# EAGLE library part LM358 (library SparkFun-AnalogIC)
Jellybean op-amp

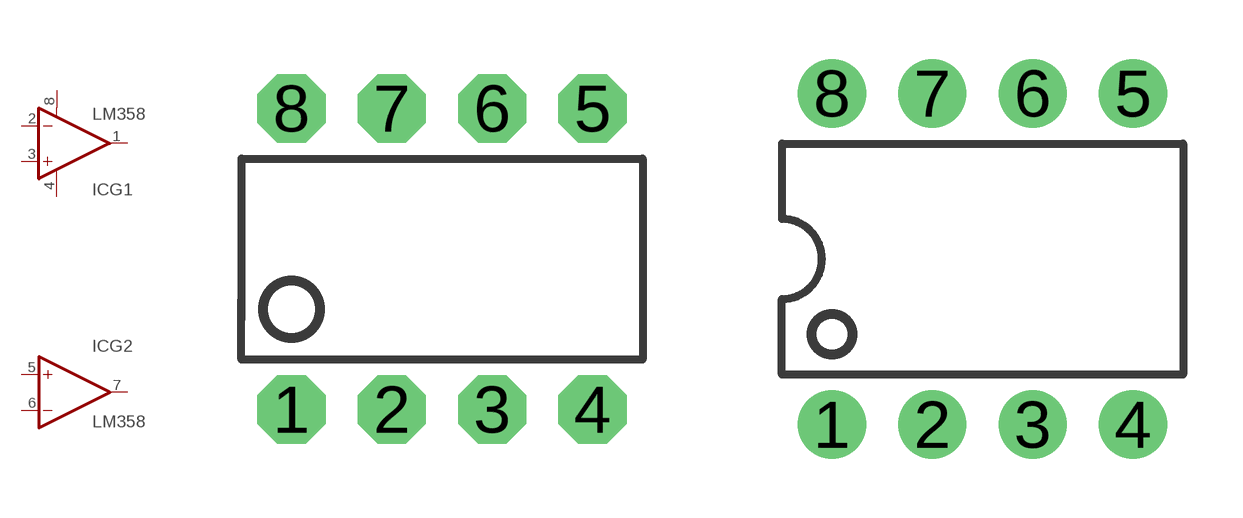
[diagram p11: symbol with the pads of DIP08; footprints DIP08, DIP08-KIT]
Designator prefix IC; gates G1=OP-AMP+- G2=OP-AMP

## LM358 (PROD_ID: IC-09172)  [DIP08]
1  G1:OUT  out
2  G1:-IN  in
3  G1:+IN  in
4  G1:V-  pwr
5  G2:+IN  in
6  G2:-IN  in
7  G2:OUT  out
8  G1:V+  pwr

## LM358KIT (PROD_ID: IC-09172)  [DIP08-KIT]
Pads as for DIP08

## Footprint DIP08 (pad centres in mm)
Dual In Line
drill 0.813 pad 1.727 octagon: 1 -3.81,-3.81; 2 -1.27,-3.81; 3 1.27,-3.81; 4 3.81,-3.81; 5 3.81,3.81; 6 1.27,3.81; 7 -1.27,3.81; 8 -3.81,3.81

## Footprint DIP08-KIT (pad centres in mm)
drill 0.813 pad 1.727: 1 -3.81,-4.191; 2 -1.27,-4.191; 3 1.27,-4.191; 4 3.81,-4.191; 5 3.81,4.191; 6 1.27,4.191; 7 -1.27,4.191; 8 -3.81,4.191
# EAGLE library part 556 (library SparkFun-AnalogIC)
Dual timer circuit (2 555 timers in one package)

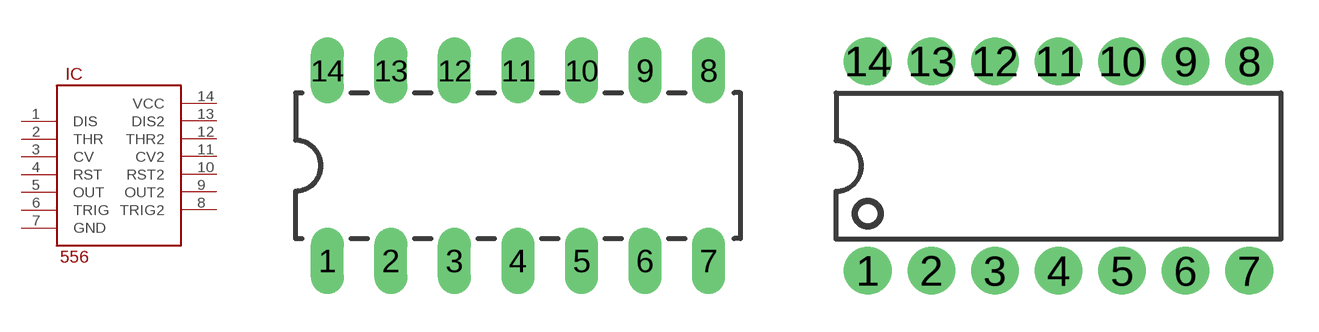
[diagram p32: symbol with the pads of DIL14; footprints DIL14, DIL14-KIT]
Designator prefix IC

## 556  [DIL14]
1  DIS
2  THR
3  CV
4  RST
5  OUT
6  TRIG
7  GND
8  TRIG2
9  OUT2
10  RST2
11  CV2
12  THR2
13  DIS2
14  VCC

## 556KIT (VALUE: 556)  [DIL14-KIT]
Pads as for DIL14

## Footprint DIL14 (pad centres in mm)
drill 0.813 long: 1 -8.89,-3.81; 2 -6.35,-3.81; 3 -3.81,-3.81; 4 -1.27,-3.81; 5 1.27,-3.81; 6 3.81,-3.81; 7 6.35,-3.81; 8 6.35,3.81; 9 3.81,3.81; 10 1.27,3.81; 11 -1.27,3.81; 12 -3.81,3.81; 13 -6.35,3.81; 14 -8.89,3.81

## Footprint DIL14-KIT (pad centres in mm)
drill 0.864 pad 1.905: 1 -8.89,-4.191; 2 -6.35,-4.191; 3 -3.81,-4.191; 4 -1.27,-4.191; 5 1.27,-4.191; 6 3.81,-4.191; 7 6.35,-4.191; 8 6.35,4.191; 9 3.81,4.191; 10 1.27,4.191; 11 -1.27,4.191; 12 -3.81,4.191; 13 -6.35,4.191; 14 -8.89,4.191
